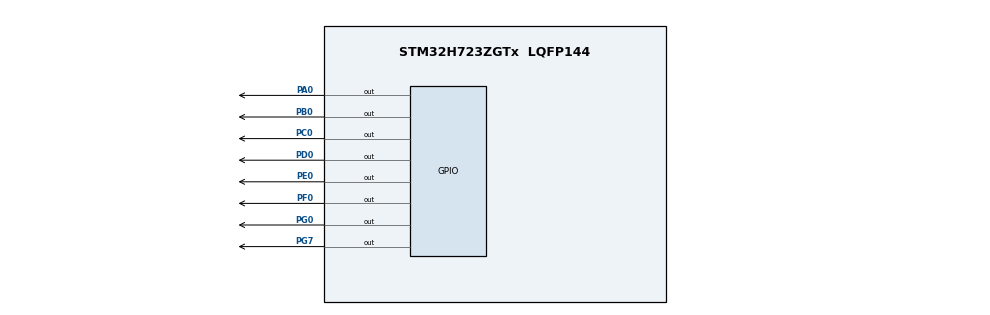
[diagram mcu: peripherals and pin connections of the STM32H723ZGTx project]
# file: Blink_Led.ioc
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CORTEX_M7.default_mode_Activation=1
Mcu.Family=STM32H7
Mcu.Name=STM32H723ZGTx
Mcu.Package=LQFP144
NVIC.PriorityGroup=NVIC_PRIORITYGROUP_4
PA0.Signal=GPIO_Output
PA13(JTMS/SWDIO).Mode=Serial_Wire
PA13(JTMS/SWDIO).Signal=DEBUG_JTMS-SWDIO
PA14(JTCK/SWCLK).Mode=Serial_Wire
PA14(JTCK/SWCLK).Signal=DEBUG_JTCK-SWCLK
PB0.Signal=GPIO_Output
PC0.Signal=GPIO_Output
PD0.Signal=GPIO_Output
PE0.Signal=GPIO_Output
PF0.Signal=GPIO_Output
PG0.Signal=GPIO_Output
PG7.Signal=GPIO_Output
ProjectManager.HeapSize=0x200
ProjectManager.StackSize=0x400
ProjectManager.TargetToolchain=STM32CubeIDE
RCC.ADCFreq_Value=129000000
RCC.APB1Freq_Value=4000000
RCC.APB2Freq_Value=4000000
RCC.APB3Freq_Value=4000000
RCC.APB4Freq_Value=4000000
RCC.CortexFreq_Value=64000000
RCC.HCLKFreq_Value=4000000
RCC.HPRE=RCC_HCLK_DIV16
RCC.SYSCLKFreq_VALUE=64000000
RCC.USBFreq_Value=129000000
VP_MEMORYMAP_VS_MEMORYMAP.Mode=CurAppReg
board=custom

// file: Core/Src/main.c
/* USER CODE BEGIN Header */
/**
  ******************************************************************************
  * @file           : main.c
  * @brief          : Main program body
  ******************************************************************************
  * @attention
  *
  * Copyright (c) 2025 STMicroelectronics.
  * All rights reserved.
  *
  * This software is licensed under terms that can be found in the LICENSE file
  * in the root directory of this software component.
  * If no LICENSE file comes with this software, it is provided AS-IS.
  *
  ******************************************************************************
  */
/* USER CODE END Header */
#include "main.h"

void SystemClock_Config(void);
static void MPU_Config(void);
static void MX_GPIO_Init(void);

int main(void)
{

  /* MPU Configuration--------------------------------------------------------*/
  MPU_Config();

  /* MCU Configuration--------------------------------------------------------*/

  /* Reset of all peripherals, Initializes the Flash interface and the Systick. */
  HAL_Init();

  /* Configure the system clock */
  SystemClock_Config();

  /* Initialize all configured peripherals */
  MX_GPIO_Init();
  /* USER CODE BEGIN 2 */
	//Xuan Truong say hi!!!
	//Xuan Truong say hi twice!!!
  /* USER CODE END 2 */
  uint32_t new_fm[1024];
  /* Infinite loop */
  /* USER CODE BEGIN WHILE */
  while (1)
  {
    //uint32_t* start_addr = (uint32_t*)0x04000000;
  // HAL_GPIO_TogglePin(GPIOF,GPIO_PIN_0 | GPIO_PIN_1 | GPIO_PIN_2 | GPIO_PIN_3 | GPIO_PIN_4 | GPIO_PIN_5 | GPIO_PIN_6 | GPIO_PIN_7 | GPIO_PIN_8 | GPIO_PIN_9 | GPIO_PIN_10 | GPIO_PIN_11 | GPIO_PIN_12 | GPIO_PIN_13 | GPIO_PIN_14 | GPIO_PIN_15);
  // HAL_GPIO_TogglePin(GPIOC,GPIO_PIN_0 | GPIO_PIN_13 | GPIO_PIN_14 | GPIO_PIN_15 | GPIO_PIN_1 | GPIO_PIN_2 | GPIO_PIN_3 | GPIO_PIN_4 | GPIO_PIN_5 | GPIO_PIN_6 | GPIO_PIN_7 |GPIO_PIN_8 | GPIO_PIN_9 | GPIO_PIN_10 | GPIO_PIN_11 | GPIO_PIN_12);
  // HAL_GPIO_TogglePin(GPIOA,GPIO_PIN_0 | GPIO_PIN_1 | GPIO_PIN_2 | GPIO_PIN_3 | GPIO_PIN_4 | GPIO_PIN_5 | GPIO_PIN_6 | GPIO_PIN_7 | GPIO_PIN_8 | GPIO_PIN_9 | GPIO_PIN_10 | GPIO_PIN_11 | GPIO_PIN_12 | GPIO_PIN_15);
  // HAL_GPIO_TogglePin(GPIOB,GPIO_PIN_0 | GPIO_PIN_1 | GPIO_PIN_2 | GPIO_PIN_10 | GPIO_PIN_11 | GPIO_PIN_12 | GPIO_PIN_13 | GPIO_PIN_14 | GPIO_PIN_15 | GPIO_PIN_3 | GPIO_PIN_4 | GPIO_PIN_5 | GPIO_PIN_6 | GPIO_PIN_7 | GPIO_PIN_8 | GPIO_PIN_9);
  // HAL_GPIO_TogglePin(GPIOG,GPIO_PIN_0|GPIO_PIN_7 | GPIO_PIN_1 | GPIO_PIN_2 | GPIO_PIN_3 | GPIO_PIN_4 | GPIO_PIN_5 | GPIO_PIN_6 | GPIO_PIN_8 | GPIO_PIN_9 | GPIO_PIN_10 | GPIO_PIN_11 | GPIO_PIN_12 | GPIO_PIN_13 | GPIO_PIN_14 | GPIO_PIN_15);
  // HAL_GPIO_TogglePin(GPIOD,GPIO_PIN_0 | GPIO_PIN_8 | GPIO_PIN_9 | GPIO_PIN_10 | GPIO_PIN_11 | GPIO_PIN_12 | GPIO_PIN_13 | GPIO_PIN_14 | GPIO_PIN_15 | GPIO_PIN_1 | GPIO_PIN_2 | GPIO_PIN_3 | GPIO_PIN_4 | GPIO_PIN_5 | GPIO_PIN_6 | GPIO_PIN_7);
  // HAL_GPIO_TogglePin(GPIOE,GPIO_PIN_0 | GPIO_PIN_1 | GPIO_PIN_2 | GPIO_PIN_3 | GPIO_PIN_4 | GPIO_PIN_5 | GPIO_PIN_6 | GPIO_PIN_7 | GPIO_PIN_8 | GPIO_PIN_9 | GPIO_PIN_10 | GPIO_PIN_11 | GPIO_PIN_12 | GPIO_PIN_13 | GPIO_PIN_14 | GPIO_PIN_15);
  HAL_GPIO_TogglePin(GPIOG,GPIO_PIN_7);
  HAL_Delay(100);
    /* USER CODE END WHILE */

  }
}

void SystemClock_Config(void)
{
  RCC_OscInitTypeDef RCC_OscInitStruct = {0};
  RCC_ClkInitTypeDef RCC_ClkInitStruct = {0};

  /** Supply configuration update enable
  */
  HAL_PWREx_ConfigSupply(PWR_LDO_SUPPLY);

  /** Configure the main internal regulator output voltage
  */
  __HAL_PWR_VOLTAGESCALING_CONFIG(PWR_REGULATOR_VOLTAGE_SCALE3);

  while(!__HAL_PWR_GET_FLAG(PWR_FLAG_VOSRDY)) {}

  /** Initializes the RCC Oscillators according to the specified parameters
  * in the RCC_OscInitTypeDef structure.
  */
  RCC_OscInitStruct.OscillatorType = RCC_OSCILLATORTYPE_HSI;
  RCC_OscInitStruct.HSIState = RCC_HSI_DIV1;
  RCC_OscInitStruct.HSICalibrationValue = 64;
  RCC_OscInitStruct.PLL.PLLState = RCC_PLL_NONE;
  if (HAL_RCC_OscConfig(&RCC_OscInitStruct) != HAL_OK)
  {
    Error_Handler();
  }

  /** Initializes the CPU, AHB and APB buses clocks
  */
  RCC_ClkInitStruct.ClockType = RCC_CLOCKTYPE_HCLK|RCC_CLOCKTYPE_SYSCLK
                              |RCC_CLOCKTYPE_PCLK1|RCC_CLOCKTYPE_PCLK2
                              |RCC_CLOCKTYPE_D3PCLK1|RCC_CLOCKTYPE_D1PCLK1;
  RCC_ClkInitStruct.SYSCLKSource = RCC_SYSCLKSOURCE_HSI;
  RCC_ClkInitStruct.SYSCLKDivider = RCC_SYSCLK_DIV1;
  RCC_ClkInitStruct.AHBCLKDivider = RCC_HCLK_DIV16;
  RCC_ClkInitStruct.APB3CLKDivider = RCC_APB3_DIV1;
  RCC_ClkInitStruct.APB1CLKDivider = RCC_APB1_DIV1;
  RCC_ClkInitStruct.APB2CLKDivider = RCC_APB2_DIV1;
  RCC_ClkInitStruct.APB4CLKDivider = RCC_APB4_DIV1;

  if (HAL_RCC_ClockConfig(&RCC_ClkInitStruct, FLASH_LATENCY_0) != HAL_OK)
  {
    Error_Handler();
  }
}

static void MX_GPIO_Init(void)
{
  GPIO_InitTypeDef GPIO_InitStruct = {0};

  /* GPIO Ports Clock Enable */
  __HAL_RCC_GPIOF_CLK_ENABLE();
  __HAL_RCC_GPIOC_CLK_ENABLE();
  __HAL_RCC_GPIOA_CLK_ENABLE();
  __HAL_RCC_GPIOB_CLK_ENABLE();
  __HAL_RCC_GPIOG_CLK_ENABLE();
  __HAL_RCC_GPIOD_CLK_ENABLE();
  __HAL_RCC_GPIOE_CLK_ENABLE();

  /*Configure GPIO pin Output Level */
  HAL_GPIO_WritePin(GPIOF, GPIO_PIN_0, GPIO_PIN_RESET);

  /*Configure GPIO pin Output Level */
  HAL_GPIO_WritePin(GPIOC, GPIO_PIN_0, GPIO_PIN_RESET);

  /*Configure GPIO pin Output Level */
  HAL_GPIO_WritePin(GPIOA, GPIO_PIN_0, GPIO_PIN_RESET);

  /*Configure GPIO pin Output Level */
  HAL_GPIO_WritePin(GPIOB, GPIO_PIN_0, GPIO_PIN_RESET);

  /*Configure GPIO pin Output Level */
  HAL_GPIO_WritePin(GPIOG, GPIO_PIN_0|GPIO_PIN_7, GPIO_PIN_RESET);

  /*Configure GPIO pin Output Level */
  HAL_GPIO_WritePin(GPIOD, GPIO_PIN_0, GPIO_PIN_RESET);

  /*Configure GPIO pin Output Level */
  HAL_GPIO_WritePin(GPIOE, GPIO_PIN_0, GPIO_PIN_RESET);

  /*Configure GPIO pin : PF0 */
  GPIO_InitStruct.Pin = GPIO_PIN_0 | GPIO_PIN_1 | GPIO_PIN_2 | GPIO_PIN_3 | GPIO_PIN_4 | GPIO_PIN_5 | GPIO_PIN_6 | GPIO_PIN_7 | GPIO_PIN_8 | GPIO_PIN_9 | GPIO_PIN_10 | GPIO_PIN_11 | GPIO_PIN_12 | GPIO_PIN_13 | GPIO_PIN_14 | GPIO_PIN_15;
  GPIO_InitStruct.Mode = GPIO_MODE_OUTPUT_PP;
  GPIO_InitStruct.Pull = GPIO_NOPULL;
  GPIO_InitStruct.Speed = GPIO_SPEED_FREQ_LOW;
  HAL_GPIO_Init(GPIOF, &GPIO_InitStruct);

  /*Configure GPIO pin : PC0 */
  GPIO_InitStruct.Pin = GPIO_PIN_0 | GPIO_PIN_13 | GPIO_PIN_14 | GPIO_PIN_15 | GPIO_PIN_1 | GPIO_PIN_2 | GPIO_PIN_3 | GPIO_PIN_4 | GPIO_PIN_5 | GPIO_PIN_6 | GPIO_PIN_7 |GPIO_PIN_8 | GPIO_PIN_9 | GPIO_PIN_10 | GPIO_PIN_11 | GPIO_PIN_12;
  GPIO_InitStruct.Mode = GPIO_MODE_OUTPUT_PP;
  GPIO_InitStruct.Pull = GPIO_NOPULL;
  GPIO_InitStruct.Speed = GPIO_SPEED_FREQ_LOW;
  HAL_GPIO_Init(GPIOC, &GPIO_InitStruct);

  /*Configure GPIO pin : PA0 */
  GPIO_InitStruct.Pin = GPIO_PIN_0 | GPIO_PIN_1 | GPIO_PIN_2 | GPIO_PIN_3 | GPIO_PIN_4 | GPIO_PIN_5 | GPIO_PIN_6 | GPIO_PIN_7 | GPIO_PIN_8 | GPIO_PIN_9 | GPIO_PIN_10 | GPIO_PIN_11 | GPIO_PIN_12 | GPIO_PIN_15;
  GPIO_InitStruct.Mode = GPIO_MODE_OUTPUT_PP;
  GPIO_InitStruct.Pull = GPIO_NOPULL;
  GPIO_InitStruct.Speed = GPIO_SPEED_FREQ_LOW;
  HAL_GPIO_Init(GPIOA, &GPIO_InitStruct);

  /*Configure GPIO pin : PB0 */
  GPIO_InitStruct.Pin = GPIO_PIN_0 | GPIO_PIN_1 | GPIO_PIN_2 | GPIO_PIN_10 | GPIO_PIN_11 | GPIO_PIN_12 | GPIO_PIN_13 | GPIO_PIN_14 | GPIO_PIN_15 | GPIO_PIN_3 | GPIO_PIN_4 | GPIO_PIN_5 | GPIO_PIN_6 | GPIO_PIN_7 | GPIO_PIN_8 | GPIO_PIN_9;
  GPIO_InitStruct.Mode = GPIO_MODE_OUTPUT_PP;
  GPIO_InitStruct.Pull = GPIO_NOPULL;
  GPIO_InitStruct.Speed = GPIO_SPEED_FREQ_LOW;
  HAL_GPIO_Init(GPIOB, &GPIO_InitStruct);

  /*Configure GPIO pins : PG0 PG7 */
  GPIO_InitStruct.Pin = GPIO_PIN_0|GPIO_PIN_7 | GPIO_PIN_1 | GPIO_PIN_2 | GPIO_PIN_3 | GPIO_PIN_4 | GPIO_PIN_5 | GPIO_PIN_6 | GPIO_PIN_8 | GPIO_PIN_9 | GPIO_PIN_10 | GPIO_PIN_11 | GPIO_PIN_12 | GPIO_PIN_13 | GPIO_PIN_14 | GPIO_PIN_15;
  GPIO_InitStruct.Mode = GPIO_MODE_OUTPUT_PP;
  GPIO_InitStruct.Pull = GPIO_NOPULL;
  GPIO_InitStruct.Speed = GPIO_SPEED_FREQ_LOW;
  HAL_GPIO_Init(GPIOG, &GPIO_InitStruct);

  /*Configure GPIO pin : PD0 */
  GPIO_InitStruct.Pin = GPIO_PIN_0 | GPIO_PIN_8 | GPIO_PIN_9 | GPIO_PIN_10 | GPIO_PIN_11 | GPIO_PIN_12 | GPIO_PIN_13 | GPIO_PIN_14 | GPIO_PIN_15 | GPIO_PIN_1 | GPIO_PIN_2 | GPIO_PIN_3 | GPIO_PIN_4 | GPIO_PIN_5 | GPIO_PIN_6 | GPIO_PIN_7;
  GPIO_InitStruct.Mode = GPIO_MODE_OUTPUT_PP;
  GPIO_InitStruct.Pull = GPIO_NOPULL;
  GPIO_InitStruct.Speed = GPIO_SPEED_FREQ_LOW;
  HAL_GPIO_Init(GPIOD, &GPIO_InitStruct);

  /*Configure GPIO pin : PE0 */
  GPIO_InitStruct.Pin = GPIO_PIN_0 | GPIO_PIN_1 | GPIO_PIN_2 | GPIO_PIN_3 | GPIO_PIN_4 | GPIO_PIN_5 | GPIO_PIN_6 | GPIO_PIN_7 | GPIO_PIN_8 | GPIO_PIN_9 | GPIO_PIN_10 | GPIO_PIN_11 | GPIO_PIN_12 | GPIO_PIN_13 | GPIO_PIN_14 | GPIO_PIN_15;
  GPIO_InitStruct.Mode = GPIO_MODE_OUTPUT_PP;
  GPIO_InitStruct.Pull = GPIO_NOPULL;
  GPIO_InitStruct.Speed = GPIO_SPEED_FREQ_LOW;
  HAL_GPIO_Init(GPIOE, &GPIO_InitStruct);

  /*AnalogSwitch Config */
  HAL_SYSCFG_AnalogSwitchConfig(SYSCFG_SWITCH_PA0, SYSCFG_SWITCH_PA0_CLOSE);

}

 /* MPU Configuration */

void MPU_Config(void)
{
  MPU_Region_InitTypeDef MPU_InitStruct = {0};

  /* Disables the MPU */
  HAL_MPU_Disable();

  /** Initializes and configures the Region and the memory to be protected
  */
  MPU_InitStruct.Enable = MPU_REGION_ENABLE;
  MPU_InitStruct.Number = MPU_REGION_NUMBER0;
  MPU_InitStruct.BaseAddress = 0x0;
  MPU_InitStruct.Size = MPU_REGION_SIZE_4GB;
  MPU_InitStruct.SubRegionDisable = 0x87;
  MPU_InitStruct.TypeExtField = MPU_TEX_LEVEL0;
  MPU_InitStruct.AccessPermission = MPU_REGION_NO_ACCESS;
  MPU_InitStruct.DisableExec = MPU_INSTRUCTION_ACCESS_DISABLE;
  MPU_InitStruct.IsShareable = MPU_ACCESS_SHAREABLE;
  MPU_InitStruct.IsCacheable = MPU_ACCESS_NOT_CACHEABLE;
  MPU_InitStruct.IsBufferable = MPU_ACCESS_NOT_BUFFERABLE;

  HAL_MPU_ConfigRegion(&MPU_InitStruct);
  /* Enables the MPU */
  HAL_MPU_Enable(MPU_PRIVILEGED_DEFAULT);

}

void Error_Handler(void)
{
  __disable_irq();
  while (1)
  {
  }
}
